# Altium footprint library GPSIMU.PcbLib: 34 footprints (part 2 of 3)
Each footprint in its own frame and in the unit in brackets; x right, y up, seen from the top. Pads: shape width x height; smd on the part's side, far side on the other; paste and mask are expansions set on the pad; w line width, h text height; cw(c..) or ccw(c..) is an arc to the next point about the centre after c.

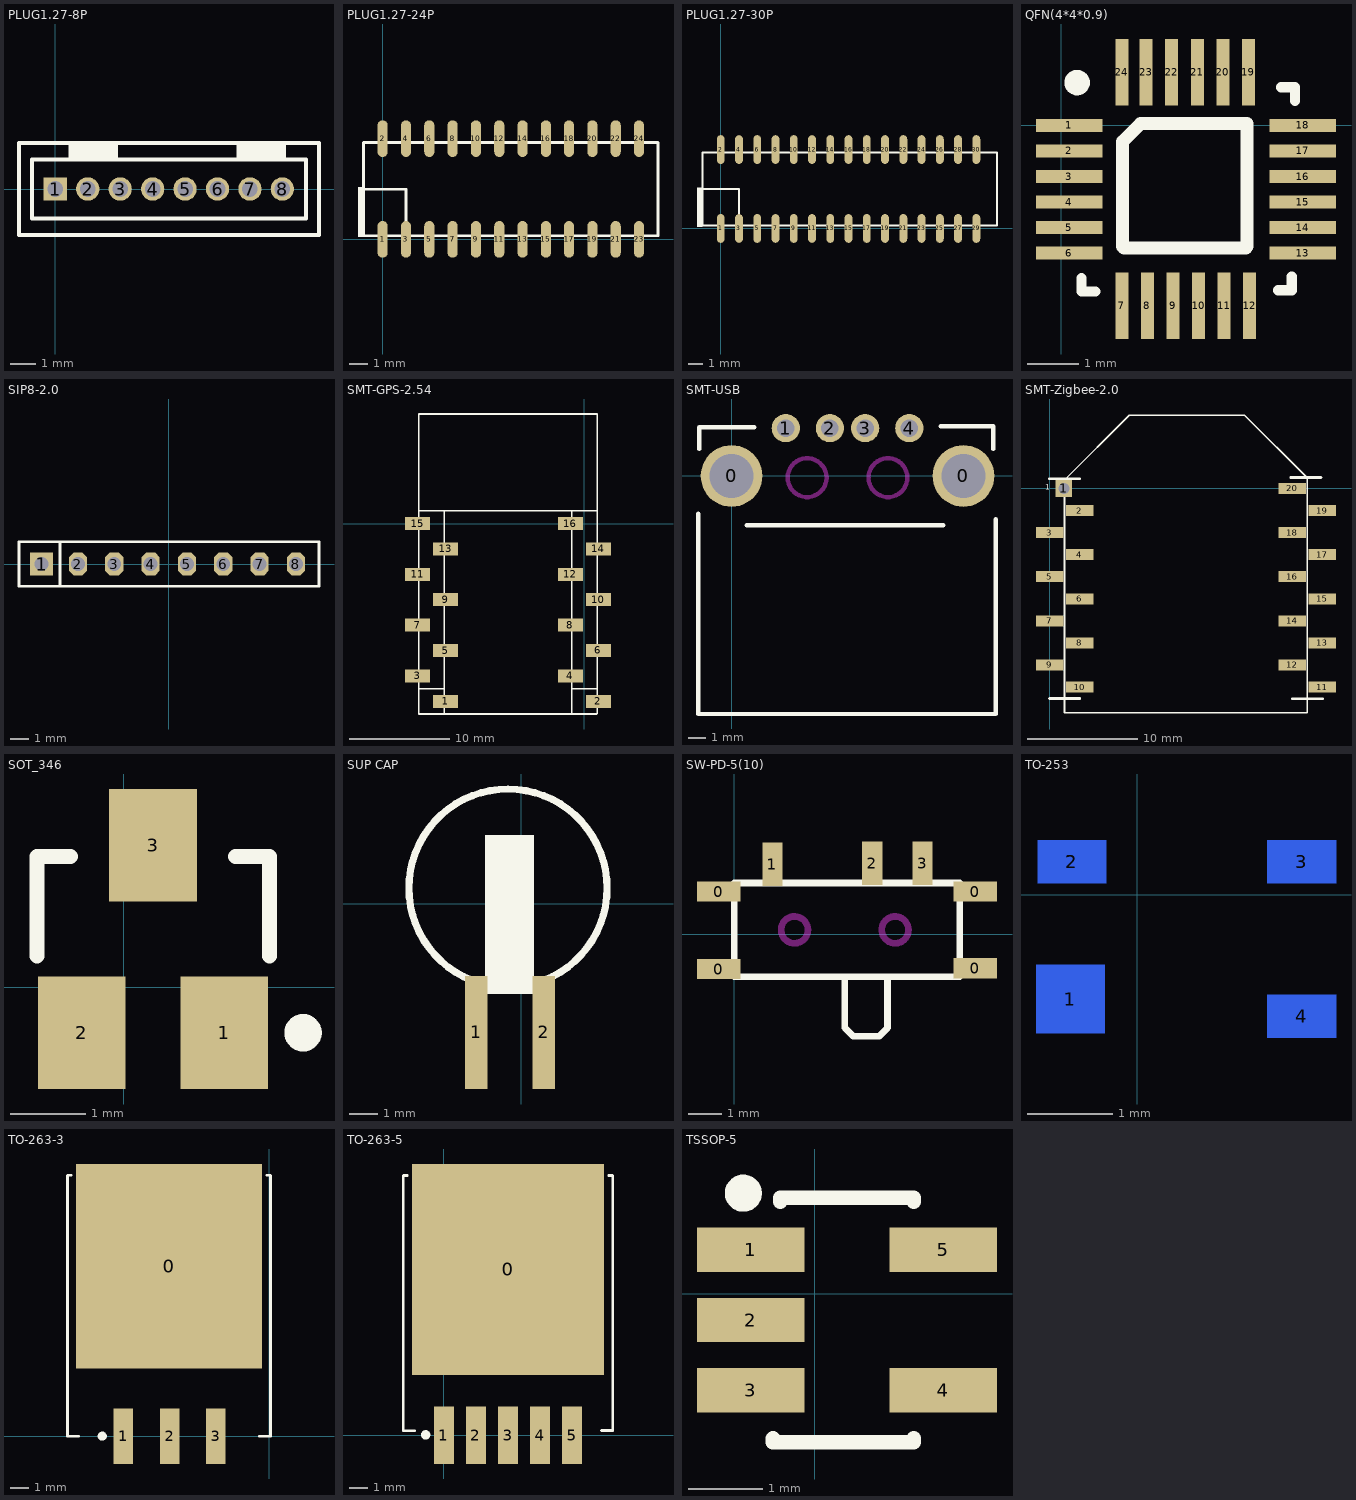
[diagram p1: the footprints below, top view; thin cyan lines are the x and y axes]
## PLUG1.27-8P [mm] "1.27mm  1*8p"
pads (8):
  rect 0.9x0.9 hole 0.6: 1(0,0)
  round 0.9 hole 0.6: 2(1.25,0) 3(2.5,0) 4(3.75,0) 5(5,0) 6(6.25,0) 7(7.5,0) 8(8.75,0)
Top Overlay:
  rectangle: 6.985,1.143 8.89,1.778
  rectangle: 0.508,1.143 2.413,1.778
  lines w0.152: -1.397,-1.778 10.16,-1.778 10.16,1.778 -1.397,1.778 -1.397,-1.778 ; -0.889,-1.143 9.652,-1.143 9.652,1.143 -0.889,1.143 -0.889,-1.143

## PLUG1.27-24P [mm]
height 1
pads (24):
  oval 0.55x2 smd: 1(-0.003,-0.015) 2(-0.003,5.467) 3(1.267,-0.015) 4(1.267,5.467) 5(2.537,-0.015) 6(2.537,5.467) 7(3.807,-0.015) 8(3.807,5.467) 9(5.077,-0.015) 10(5.077,5.467) 11(6.347,-0.015) 12(6.347,5.467) 13(7.617,-0.015) 14(7.617,5.467) 15(8.887,-0.015) 16(8.887,5.467) 17(10.147,-0.015) 18(10.147,5.467) 19(11.417,-0.015) 20(11.417,5.467) 21(12.687,-0.015) 22(12.687,5.467) 23(13.957,-0.015) 24(13.957,5.467)
Top Overlay:
  rectangle: -1.344,0.101 -0.963,2.844
  lines w0.152: -1.023,2.717 1.267,2.717 1.267,0.177 ; -1.038,0.177 14.99,0.177 14.99,5.257 -1.038,5.257 -1.038,0.177

## PLUG1.27-30P [mm]
pads (30):
  oval 0.55x2 smd: 1(0,0) 2(0,5.483) 3(1.27,0) 4(1.27,5.483) 5(2.54,0) 6(2.54,5.483) 7(3.81,0) 8(3.81,5.483) 9(5.08,0) 10(5.08,5.483) 11(6.35,0) 12(6.35,5.483) 13(7.62,0) 14(7.62,5.483) 15(8.89,0) 16(8.89,5.483) 17(10.16,0) 18(10.16,5.483) 19(11.43,0) 20(11.43,5.483) 21(12.7,0) 22(12.7,5.483) 23(13.97,0) 24(13.97,5.483) 25(15.24,0) 26(15.24,5.483) 27(16.51,0) 28(16.51,5.483) 29(17.78,0) 30(17.78,5.483)
Top Overlay:
  rectangle: -1.651,0.09 -1.27,2.833
  lines w0.152: -1.27,2.732 1.27,2.732 1.27,0.192 ; -1.27,0.192 19.218,0.192 19.218,5.272 -1.27,5.272 -1.27,0.192

## PULG1.25-8P [mm]

## QFN(4*4*0.9) [mil]
pads (24):
  rect 51.18x10 smd: 1(6,0) 2(6,-19.68) 3(6,-39.37) 4(6,-59.06) 5(6,-78.74) 6(6,-98.43) 13(186,-98.43) 14(186,-78.74) 15(186,-59.06) 16(186,-39.37) 17(186,-19.68) 18(186,0)
  rect 10x51.18 smd: 7(46.64,-139) 8(66.32,-139) 9(86.01,-139) 10(105.69,-139) 11(125.38,-139) 12(145.06,-139) 19(144.06,41) 20(124.38,41) 21(104.69,41) 22(85.01,41) 23(65.32,41) 24(46.64,41)
Top Overlay:
  circle w9.84: c12.08,33 r4.92
  lines w7.87: 15.47,-117.58 15.47,-128 26,-128 ; 167,-127 177.42,-127 177.42,-116.47 ; 169.47,29.42 180,29.42 180,19
  lines w10: 47.11,-93.47 47.11,-12.47 61.11,1.53 143.11,1.53 143.11,-93.47 ; 48.11,-94.47 142.11,-94.47

## SIP8-2.0 [mm]
height 1
pads (8):
  rect 1.27x1.27 hole 0.762: 1(-7,0)
  oct 1x1.27 hole 0.762: 2(-5,0) 3(-3,0) 4(-1,0) 5(1,0) 6(3,0) 7(5,0) 8(7,0)
Top Overlay:
  lines w0.152: -5.984,-1.219 -5.984,1.219 ; 8.27,1.194 8.27,-1.219 -8.245,-1.219 -8.245,1.219 8.27,1.219

## SMT-GPS-2.54 [mm]
height 1
pads (16):
  rect 2.5x1.3 smd: 1(-13.881,-17.784) 2(1.4,-17.78) 3(-16.681,-15.244) 4(-1.4,-15.24) 5(-13.881,-12.704) 6(1.4,-12.7) 7(-16.681,-10.164) 8(-1.4,-10.16) 9(-13.881,-7.624) 10(1.4,-7.62) 11(-16.681,-5.084) 12(-1.4,-5.08) 13(-13.881,-2.544) 14(1.4,-2.54) 15(-16.681,-0.004) 16(-1.4,0)
Top Overlay:
  lines w0.152: -16.551,-19.054 -14.032,-19.054 -14.032,1.266 -16.551,1.266 ; -16.551,-16.514 -14.011,-16.514 ; -1.27,-16.51 1.27,-16.51 ; 1.272,1.266 1.272,-19.05 -1.27,-19.05 -1.27,1.27 1.272,1.27
  lines w0.154: -16.548,1.266 1.272,1.266 1.272,10.958 -16.548,10.958 -16.548,-19.054 1.257,-19.054

## SMT-USB [mm]
height 1
pads (6):
  round 3.5 hole 2.5: 0(0,0) 0(13.14,0)
  round 1.6 hole 1: 1(3.07,2.71) 2(5.57,2.71) 3(7.57,2.71) 4(10.07,2.71)
Top Overlay:
  lines w0.254: -1.893,-2.137 -1.893,-13.494 14.974,-13.494 14.959,-2.442 ; -1.832,1.526 -1.832,2.748 1.282,2.748 ; 0.855,-2.809 11.998,-2.809 ; 11.845,2.809 14.837,2.809 14.837,1.526
Keep-Out Layer:
  circle w0.254: c4.28,-0.1 r1.1
  circle w0.254: c8.86,-0.1 r1.1

## SMT-Zigbee-2.0 [mm] "2.0MM"
height 1
pads (20):
  rect 1.5x1.5 hole 1: 1(1.27,0)
  rect 2.5x1 smd: 2(2.7,-2) 3(0,-4) 4(2.7,-6) 5(0,-8) 6(2.7,-10) 7(0,-12) 8(2.7,-14) 9(0,-16) 10(2.7,-18) 11(24.7,-18) 12(22,-16) 13(24.7,-14) 14(22,-12) 15(24.7,-10) 16(22,-8) 17(24.7,-6) 18(22,-4) 19(24.7,-2) 20(22,0)
Top Overlay:
  lines w0.152: 23.346,-20.32 1.335,-20.32 1.335,0.762 7.205,6.626 17.687,6.621 23.35,0.958 23.35,0.782 ; 23.35,-20.32 23.35,0.9
  lines w0.254: -0.048,0.878 2.697,0.878 ; -0.032,-19.05 2.712,-19.05 ; 21.845,1.008 24.589,1.008 ; 21.994,-19.065 24.738,-19.065
  text "1" at -0.39,-0.111 h0.51

## SOT_346 [mm] "RB420D"
height 1
pads (3):
  rect 1.17x1.5 smd: 1(1.341,-0.61) 2(-0.559,-0.61) 3(0.391,1.89)
Top Overlay:
  circle w0.25: c2.39,-0.61 r0.125
  lines w0.2: -1.159,0.41 -1.159,1.74 -0.709,1.74 ; 1.491,1.74 1.941,1.74 1.941,0.41

## SUP CAP [mm] "0.2MM"
height 1
pads (2):
  rect 0.8x4 smd: 1(-1.595,-4.549) 2(0.788,-4.549)
Top Overlay:
  circle w0.254: c-0.474,0.548 r3.5
  rectangle: -1.283,-3.195 0.448,2.42

## SW-PD-5(10) [mm]
height 1
pads (7):
  rect 1.3x0.6 smd: 0(-0.457,-1.041) 0(-0.457,1.27) 0(7.188,-1.016) 0(7.188,1.27)
  rect 0.6x1.3 smd: 1(1.143,2.083) 2(4.118,2.108) 3(5.618,2.108)
Top Overlay:
  lines w0.2: 3.302,-1.27 3.302,-2.794 3.556,-3.048 4.318,-3.048 4.572,-2.794 4.572,-1.27 ; 6.7,1.524 0,1.524 0,-1.27 6.731,-1.27 6.731,1.524
Keep-Out Layer:
  circle w0.2: c1.8,0.127 r0.4
  circle w0.2: c4.8,0.127 r0.4

## TO-253 [mm]
height 1
pads (4):
  rect 0.8x0.8 smd far side: 1(-0.781,-1.219)
  rect 0.8x0.5 smd far side: 2(-0.761,0.381) 3(1.919,0.381) 4(1.919,-1.419)
Bottom Overlay:
  circle w0.25: c0.339,-1.504 r0.125
  lines w0.152: -0.101,-2.019 -0.101,0.961 ; -0.101,-2.016 1.21,-2.016 1.21,0.981 ; -0.101,0.981 1.199,0.981

## TO-263-3 [mil]
pads (4):
  rect 400x440 smd: 0(-216.14,366)
  rect 42x120 smd: 1(-315,0) 2(-215,0) 3(-115,0)
Top Overlay:
  circle w9.84: c-359.92,0 r4.92
  lines w5.91: -434.65,561.5 -434.65,0 -410.63,0 ; -434.25,561.73 -426.38,561.73 ; -21.26,0 2.36,0 2.36,561.5 ; -5.91,561.73 1.97,561.73

## TO-263-5 [mil]
height 39.37
pads (6):
  rect 400x440 smd: 0(133.86,346)
  rect 42x120 smd: 1(0,0) 2(66.93,0) 3(133.86,0) 4(200.79,0) 5(267.72,0)
Top Overlay:
  circle w9.84: c-37.99,0.79 r4.92
  lines w5.91: -84.65,10 -84.65,541.5 ; -84.25,9.45 -60.63,9.45 ; -84.25,541.73 -76.38,541.73 ; 328.74,10 352.36,10 352.36,541.5 ; 344.09,541.73 351.97,541.73

## TSSOP-5 [mm]
height 1
pads (5):
  rect 1.45x0.6 smd: 1(-0.864,0.595) 2(-0.864,-0.355) 3(-0.864,-1.305) 4(1.736,-1.305) 5(1.736,0.595)
Top Overlay:
  circle w0.25: c-0.964,1.357 r0.125
  lines w0.2: -0.564,-1.955 -0.564,-2.005 1.336,-2.005 1.336,-1.955 ; -0.464,1.245 -0.464,1.295 1.336,1.295 1.336,1.245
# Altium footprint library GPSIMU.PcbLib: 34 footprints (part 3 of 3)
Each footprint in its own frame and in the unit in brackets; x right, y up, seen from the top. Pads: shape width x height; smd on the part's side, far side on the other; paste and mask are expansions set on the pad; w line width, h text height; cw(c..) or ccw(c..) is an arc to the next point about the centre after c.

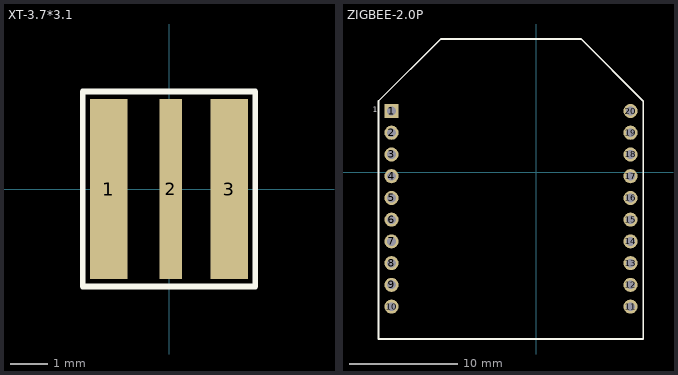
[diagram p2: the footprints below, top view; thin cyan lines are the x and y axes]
## XT-3.7*3.1 [mm] "XT-(3.7*3.1*1.5)"
height 1
pads (3):
  rect 1x4.8 smd: 1(-1.6,0) 3(1.6,0)
  rect 0.6x4.8 smd: 2(0.051,0)
Top Overlay:
  lines w0.15: -2.3,-2.6 2.3,-2.6 2.3,2.6 -2.3,2.6 -2.3,-2.6

## ZIGBEE-2.0P [mm]
pads (20):
  rect 1.3x1.3 hole 0.8: 1(-13.317,5.614)
  round 1.3 hole 0.8: 2(-13.317,3.614) 3(-13.317,1.614) 4(-13.317,-0.386) 5(-13.317,-2.386) 6(-13.317,-4.386) 7(-13.317,-6.386) 8(-13.317,-8.386) 9(-13.317,-10.386) 10(-13.317,-12.386) 11(8.683,-12.386) 12(8.683,-10.386) 13(8.683,-8.386) 14(8.683,-6.386) 15(8.683,-4.386) 16(8.683,-2.386) 17(8.683,-0.386) 18(8.683,1.614) 19(8.683,3.614) 20(8.683,5.614)
Top Overlay:
  lines w0.152: -14.507,-15.367 -14.507,6.529 -8.79,12.241 4.143,12.234 9.863,6.514 9.863,-15.367 -14.507,-15.367
  text "1" at -15.057,5.503 h0.51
